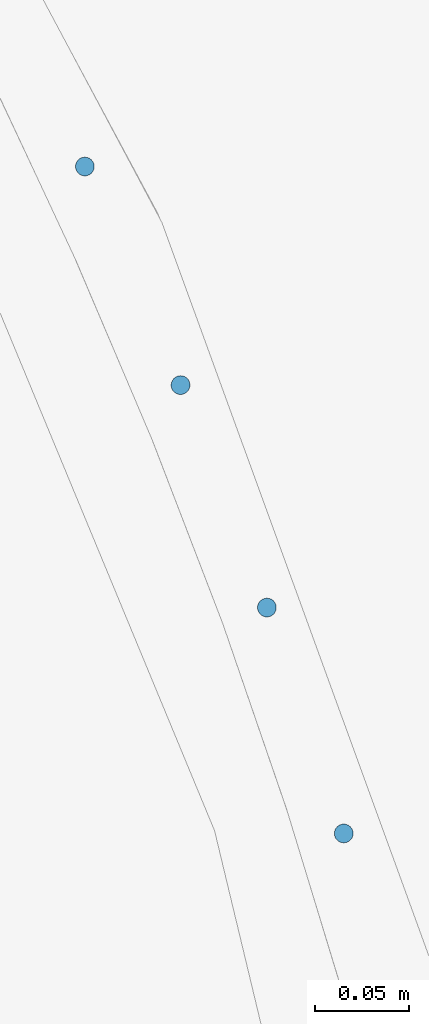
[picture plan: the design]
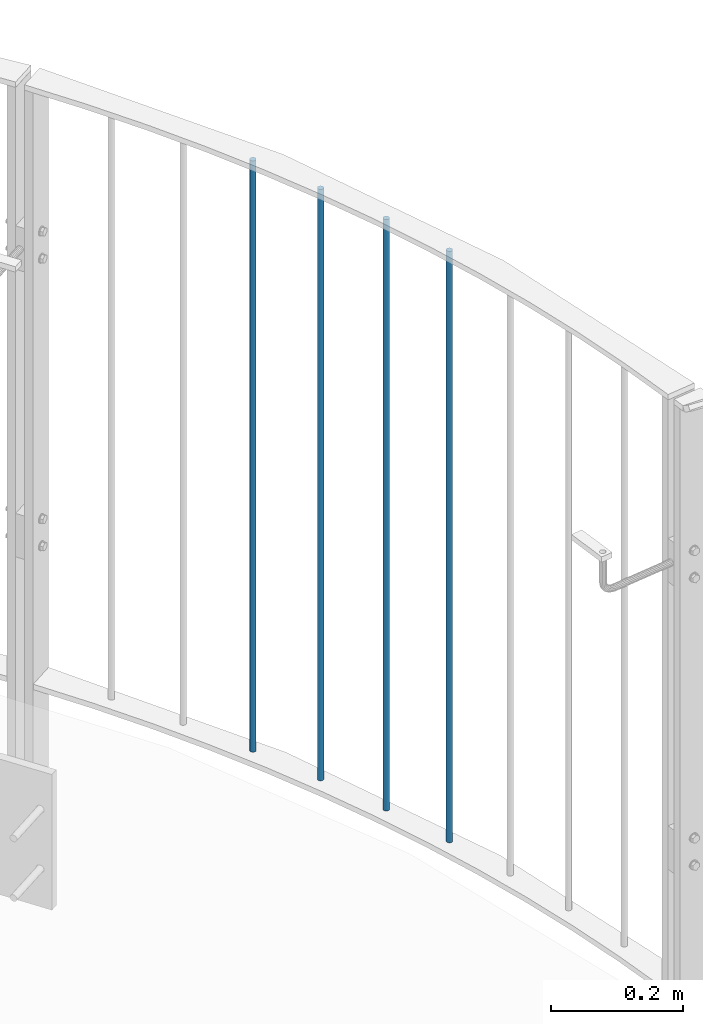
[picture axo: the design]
# One storey, part 78 of 296: 4 columns.
"""IFC2X3 building model written with IfcOpenShell, lengths in millimetres."""

from ifc_helpers import new_model, entity, si_unit, converted_unit, frame, origin, origin_with_axes, origin_2d, place, context, project, spatial, circle, extrude, material, element, save


model = new_model("IFC2X3")

# Units and contexts
model_context = context("Model", 3, precision=1e-09, world=origin_with_axes())
ifc_project = project(units=[si_unit("LENGTHUNIT", "METRE", prefix="MILLI"), si_unit("AREAUNIT", "SQUARE_METRE"), si_unit("VOLUMEUNIT", "CUBIC_METRE"), converted_unit("PLANEANGLEUNIT", "DEGREE", entity("IfcPlaneAngleMeasure", 0.01745329), si_unit("PLANEANGLEUNIT", "RADIAN"), dimensions=[0, 0, 0, 0, 0, 0, 0])], contexts=[model_context])

# Site, building, storey
site_placement = place(None, origin_with_axes())
site = spatial("IfcSite", under=ifc_project, at=site_placement, CompositionType="ELEMENT")
building_placement = place(site_placement, origin_with_axes())
building = spatial("IfcBuilding", under=site, at=building_placement, Name="1", CompositionType="ELEMENT")
storey_placement = place(building_placement, origin_with_axes())
storey = spatial("IfcBuildingStorey", under=building, at=storey_placement, Name="Default Storey", CompositionType="ELEMENT", Elevation=0.0)

# Columns
ifc_material = material(Name="S235JR")
for number, where, z_axis, x_axis in (
    (1, (5775.561227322, 802.43428571, 7350.0), (0.0, 0.0, -1.0), (0.0, 1.0, 0.0)),
    (2, (5734.68182338, 922.63019603, 7350.0), (0.0, 0.0, -1.0), (0.0, 1.0, 0.0)),
    (3, (5688.736821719, 1040.982379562, 7350.0), (0.0, 0.0, -1.0), (0.0, 1.0, 0.0)),
    (4, (5637.809056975, 1157.277458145, 7350.0), (0.0, 0.0, -1.0), (0.0, 1.0, 0.0)),
):
    element("IfcColumn", number, at=place(None, frame(where, z_axis=z_axis, x_axis=x_axis)), inside=storey, material=ifc_material, context=model_context, shape_type="SweptSolid", body=[
        extrude(circle(Radius=5.0, at=origin_2d()), origin(), (0.0, 0.0, -1.0), 1090.0),
    ])

save(model, "model.ifc")
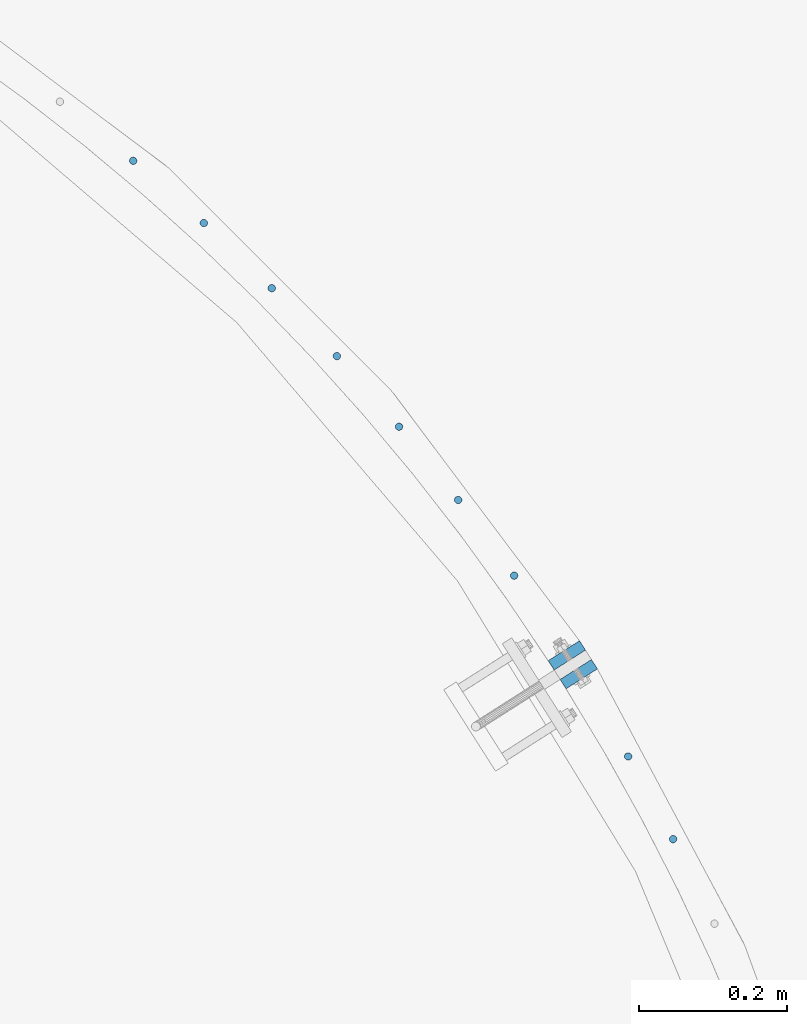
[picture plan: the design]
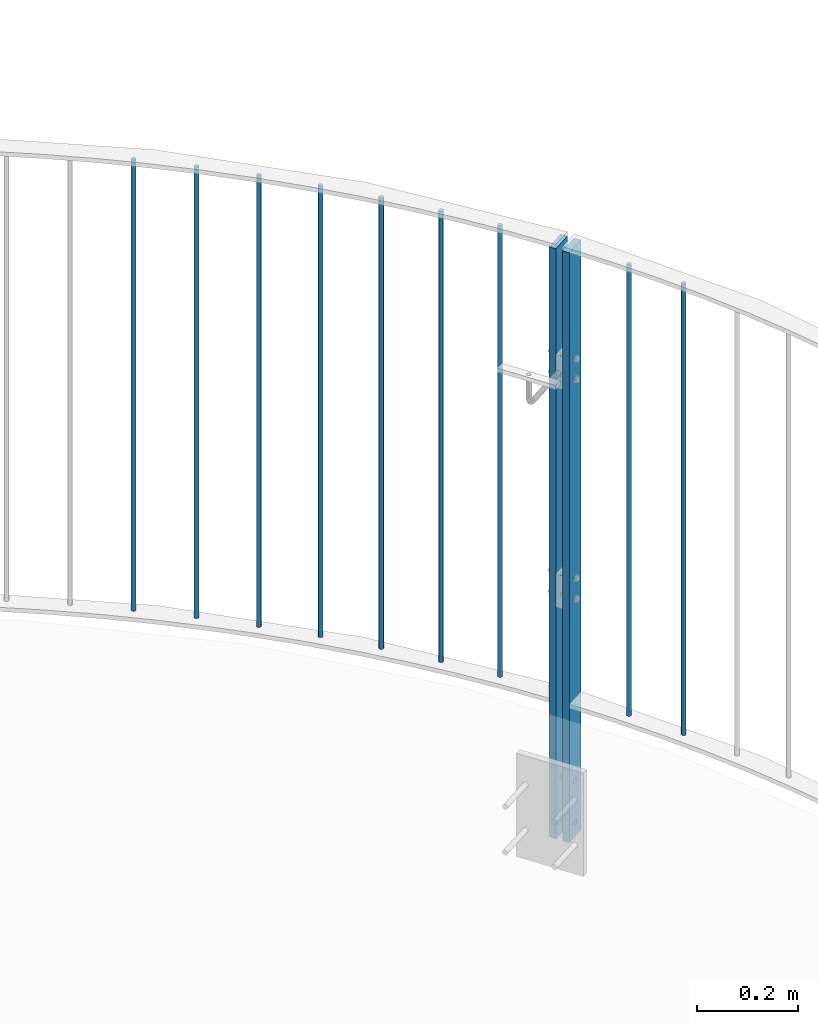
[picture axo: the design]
# One storey, part 92 of 296: 11 columns, 12 openings.
"""IFC2X3 building model written with IfcOpenShell, lengths in millimetres."""

from ifc_helpers import new_model, entity, si_unit, converted_unit, frame, frame_2d, origin, origin_with_axes, origin_2d, place, context, project, spatial, rectangle, circle, extrude, material, element, save


model = new_model("IFC2X3")

# Units and contexts
model_context = context("Model", 3, precision=1e-09, world=origin_with_axes())
ifc_project = project(units=[si_unit("LENGTHUNIT", "METRE", prefix="MILLI"), si_unit("AREAUNIT", "SQUARE_METRE"), si_unit("VOLUMEUNIT", "CUBIC_METRE"), converted_unit("PLANEANGLEUNIT", "DEGREE", entity("IfcPlaneAngleMeasure", 0.01745329), si_unit("PLANEANGLEUNIT", "RADIAN"), dimensions=[0, 0, 0, 0, 0, 0, 0])], contexts=[model_context])

# Site, building, storey
site_placement = place(None, origin_with_axes())
site = spatial("IfcSite", under=ifc_project, at=site_placement, CompositionType="ELEMENT")
building_placement = place(site_placement, origin_with_axes())
building = spatial("IfcBuilding", under=site, at=building_placement, Name="1", CompositionType="ELEMENT")
storey_placement = place(building_placement, origin_with_axes())
storey = spatial("IfcBuildingStorey", under=building, at=storey_placement, Name="Default Storey", CompositionType="ELEMENT", Elevation=0.0)

# Columns
ifc_material = material(Name="S235JR")
for number, where, z_axis, x_axis in (
    (1, (5581.990347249, 1271.305762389, 7350.0), (0.0, 0.0, -1.0), (0.0, 1.0, 0.0)),
    (2, (5521.381328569, 1382.861709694, 7350.0), (0.0, 0.0, -1.0), (0.0, 1.0, 0.0)),
    (3, (5367.595410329, 1626.727106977, 7350.0), (0.0, 0.0, -1.0), (-0.422618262, 0.906307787, 0.0)),
    (4, (5292.105864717, 1728.803113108, 7350.0), (0.0, 0.0, -1.0), (-0.422618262, 0.906307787, 0.0)),
    (5, (5212.351130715, 1827.582488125, 7350.0), (0.0, 0.0, -1.0), (-0.422618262, 0.906307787, 0.0)),
    (6, (5128.474998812, 1922.887141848, 7350.0), (0.0, 0.0, -1.0), (-0.422618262, 0.906307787, 0.0)),
    (7, (5040.628690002, 2014.545248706, 7350.0), (0.0, 0.0, -1.0), (-0.422618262, 0.906307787, 0.0)),
    (8, (4948.970583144, 2102.391557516, 7350.0), (0.0, 0.0, -1.0), (-0.422618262, 0.906307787, 0.0)),
    (9, (4853.66592942, 2186.267689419, 7350.0), (0.0, 0.0, -1.0), (-0.422618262, 0.906307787, 0.0)),
):
    element("IfcColumn", number, at=place(None, frame(where, z_axis=z_axis, x_axis=x_axis)), inside=storey, material=ifc_material, context=model_context, shape_type="SweptSolid", body=[
        extrude(circle(Radius=5.0, at=origin_2d()), origin(), (0.0, 0.0, -1.0), 1090.0),
    ])

# Column, openings
column_1_placement = place(None, frame((5454.799917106, 1493.87495727, 7015.001), z_axis=(0.0, 0.0, -1.0), x_axis=(-0.537299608, 0.843391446, 0.0)))
column_1 = element("IfcColumn", 10, at=column_1_placement, inside=storey, material=ifc_material, context=model_context, shape_type="SweptSolid", body=[
    extrude(rectangle(XDim=15.0, YDim=50.0, at=origin_2d()), origin(), (0.0, 0.0, -1.0), 1424.999),
])
opening_1_placement = place(column_1_placement, frame((8.0, 7.001, -135.0), z_axis=(1.0, 0.0, 0.0), x_axis=(0.0, 1.0, 0.0)))
element("IfcOpeningElement", 11, at=opening_1_placement, cuts=column_1, ObjectType="Opening", context=model_context, shape_type="SweptSolid", body=[
    extrude(circle(Radius=7.001, at=frame_2d((-7.001, 0.0), x_axis=(1.0, 0.0))), origin(), (0.0, 0.0, -1.0), 16.0),
])
opening_2_placement = place(column_1_placement, frame((8.0, 7.001, -35.0), z_axis=(1.0, 0.0, 0.0), x_axis=(0.0, 1.0, 0.0)))
element("IfcOpeningElement", 12, at=opening_2_placement, cuts=column_1, ObjectType="Opening", context=model_context, shape_type="SweptSolid", body=[
    extrude(circle(Radius=7.001, at=frame_2d((-7.001, 0.0), x_axis=(1.0, 0.0))), origin(), (0.0, 0.0, -1.0), 16.0),
])
opening_3_placement = place(column_1_placement, frame((8.0, 5.001, -1154.999999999), z_axis=(1.0, 0.0, 0.0), x_axis=(0.0, 1.0, 0.0)))
element("IfcOpeningElement", 13, at=opening_3_placement, cuts=column_1, ObjectType="Opening", context=model_context, shape_type="SweptSolid", body=[
    extrude(circle(Radius=5.001, at=frame_2d((-5.001, 0.0), x_axis=(1.0, 0.0))), origin(), (0.0, 0.0, -1.0), 16.0),
])
opening_4_placement = place(column_1_placement, frame((8.0, 5.001, -1104.999999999), z_axis=(1.0, 0.0, 0.0), x_axis=(0.0, 1.0, 0.0)))
element("IfcOpeningElement", 14, at=opening_4_placement, cuts=column_1, ObjectType="Opening", context=model_context, shape_type="SweptSolid", body=[
    extrude(circle(Radius=5.001, at=frame_2d((-5.001, 0.0), x_axis=(1.0, 0.0))), origin(), (0.0, 0.0, -1.0), 16.0),
])
opening_5_placement = place(column_1_placement, frame((8.0, 5.001, -624.999999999), z_axis=(1.0, 0.0, 0.0), x_axis=(0.0, 1.0, 0.0)))
element("IfcOpeningElement", 15, at=opening_5_placement, cuts=column_1, ObjectType="Opening", context=model_context, shape_type="SweptSolid", body=[
    extrude(circle(Radius=5.001, at=frame_2d((-5.001, 0.0), x_axis=(1.0, 0.0))), origin(), (0.0, 0.0, -1.0), 16.0),
])
opening_6_placement = place(column_1_placement, frame((8.0, 5.001, -574.999999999), z_axis=(1.0, 0.0, 0.0), x_axis=(0.0, 1.0, 0.0)))
element("IfcOpeningElement", 16, at=opening_6_placement, cuts=column_1, ObjectType="Opening", context=model_context, shape_type="SweptSolid", body=[
    extrude(circle(Radius=5.001, at=frame_2d((-5.001, 0.0), x_axis=(1.0, 0.0))), origin(), (0.0, 0.0, -1.0), 16.0),
])

column_2_placement = place(None, frame((5438.680928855, 1519.176700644, 7015.001), z_axis=(0.0, 0.0, 1.0), x_axis=(0.537299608, -0.843391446, 0.0)))
column_2 = element("IfcColumn", 17, at=column_2_placement, inside=storey, material=ifc_material, context=model_context, shape_type="SweptSolid", body=[
    extrude(rectangle(XDim=15.0, YDim=50.0, at=origin_2d()), origin(), (0.0, 0.0, 1.0), 1424.999),
])
opening_7_placement = place(column_2_placement, frame((-8.0, 7.001, 135.0), z_axis=(-1.0, 0.0, 0.0), x_axis=(0.0, -1.0, 0.0)))
element("IfcOpeningElement", 18, at=opening_7_placement, cuts=column_2, ObjectType="Opening", context=model_context, shape_type="SweptSolid", body=[
    extrude(circle(Radius=7.001, at=frame_2d((7.001, 0.0), x_axis=(1.0, 0.0))), origin(), (0.0, 0.0, -1.0), 16.0),
])
opening_8_placement = place(column_2_placement, frame((-8.0, 7.001, 35.0), z_axis=(-1.0, 0.0, 0.0), x_axis=(0.0, -1.0, 0.0)))
element("IfcOpeningElement", 19, at=opening_8_placement, cuts=column_2, ObjectType="Opening", context=model_context, shape_type="SweptSolid", body=[
    extrude(circle(Radius=7.001, at=frame_2d((7.001, 0.0), x_axis=(1.0, 0.0))), origin(), (0.0, 0.0, -1.0), 16.0),
])
opening_9_placement = place(column_2_placement, frame((-8.0, 5.001, 624.999999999), z_axis=(-1.0, 0.0, 0.0), x_axis=(0.0, -1.0, 0.0)))
element("IfcOpeningElement", 20, at=opening_9_placement, cuts=column_2, ObjectType="Opening", context=model_context, shape_type="SweptSolid", body=[
    extrude(circle(Radius=5.001, at=frame_2d((5.001, 0.0), x_axis=(1.0, 0.0))), origin(), (0.0, 0.0, -1.0), 16.0),
])
opening_10_placement = place(column_2_placement, frame((-8.0, 5.001, 574.999999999), z_axis=(-1.0, 0.0, 0.0), x_axis=(0.0, -1.0, 0.0)))
element("IfcOpeningElement", 21, at=opening_10_placement, cuts=column_2, ObjectType="Opening", context=model_context, shape_type="SweptSolid", body=[
    extrude(circle(Radius=5.001, at=frame_2d((5.001, 0.0), x_axis=(1.0, 0.0))), origin(), (0.0, 0.0, -1.0), 16.0),
])
opening_11_placement = place(column_2_placement, frame((-8.0, 5.001, 1154.999999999), z_axis=(-1.0, 0.0, 0.0), x_axis=(0.0, -1.0, 0.0)))
element("IfcOpeningElement", 22, at=opening_11_placement, cuts=column_2, ObjectType="Opening", context=model_context, shape_type="SweptSolid", body=[
    extrude(circle(Radius=5.001, at=frame_2d((5.001, 0.0), x_axis=(1.0, 0.0))), origin(), (0.0, 0.0, -1.0), 16.0),
])
opening_12_placement = place(column_2_placement, frame((-8.0, 5.001, 1104.999999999), z_axis=(-1.0, 0.0, 0.0), x_axis=(0.0, -1.0, 0.0)))
element("IfcOpeningElement", 23, at=opening_12_placement, cuts=column_2, ObjectType="Opening", context=model_context, shape_type="SweptSolid", body=[
    extrude(circle(Radius=5.001, at=frame_2d((5.001, 0.0), x_axis=(1.0, 0.0))), origin(), (0.0, 0.0, -1.0), 16.0),
])

save(model, "model.ifc")
